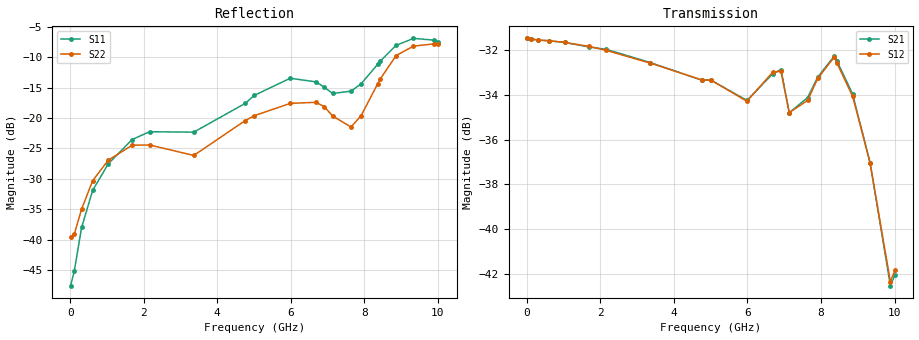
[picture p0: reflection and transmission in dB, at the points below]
! Device ID: PE43705
! Serial: 1
! Insertion: A
! Impedance: 50 ohm
! Temp: 25C
! VDD: 3.400V
! Attenuation Step: 30.50dB
#  Hz  S  RI  R  50
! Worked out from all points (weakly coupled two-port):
!   401 points, 10 MHz to 10.01 GHz, reference 50 ohm
!   highest |S21| = -31.47 dB at 10 MHz (marker M1); lowest = -42.5 dB at 9.885 GHz (marker M2)
!   lowest |S11| = -47.5 dB at 10 MHz (marker M3), VSWR 1.01, Z = 49.6 + j0.0403 ohm
!   |S11| at or under -10 dB: start of sweep to 8.525 GHz
!   |S22| runs from -39.6 to -7.8 dB; largest |S21 - S12| = 0.00087
!   S11 on the Smith chart (normalised r, x): 10 MHz: 0.99, +0.00; 4.76 GHz: 0.79, +0.12; 8.435 GHz: 0.79, +0.50; 9.335 GHz: 0.51, +0.52; 10.01 GHz: 0.46, +0.30
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1e7  -0.00419 0.000406  0.0267 -0.0001  0.0267 -0.000126  -0.0106 0.000549
1.1e8  -0.00389 0.00394  0.0266 -0.000711  0.0266 -0.00072  -0.00985 0.00519
3.1e8  -0.00643 0.0109  0.0264 -0.00193  0.0264 -0.00193  -0.0116 0.0136
6.1e8  -0.0161 0.0197  0.0261 -0.00375  0.0261 -0.00377  -0.0189 0.024
1.035e9  -0.0362 0.0214  0.0254 -0.00617  0.0254 -0.00621  -0.0344 0.0291
1.685e9  -0.066 0.00874  0.0237 -0.00953  0.0238 -0.0095  -0.0553 0.0227
2.16e9  -0.0769 -0.00592  0.0223 -0.0118  0.0222 -0.0117  -0.0586 0.0132
3.36e9  -0.0763 -0.00546  0.0173 -0.016  0.0173 -0.0159  -0.0467 0.0157
4.76e9  -0.1106 0.0718  0.0121 -0.0178  0.0123 -0.0177  -0.0783 0.0542
5.01e9  -0.1265 0.0868  0.0118 -0.018  0.0118 -0.018  -0.0867 0.0583
5.985e9  -0.181 0.11  0.00771 -0.0178  0.00773 -0.0177  -0.1149 0.0646
6.685e9  -0.1727 0.0962  0.00703 -0.0211  0.00704 -0.0213  -0.1238 0.0523
6.91e9  -0.154 0.0907  0.00387 -0.0224  0.00393 -0.0222  -0.1136 0.0493
7.135e9  -0.1394 0.0763  0.00334 -0.0179  0.00336 -0.0179  -0.0916 0.0491
7.635e9  -0.0907 0.1389  0.00384 -0.0193  0.0039 -0.019  -0.0499 0.0679
7.91e9  -0.0566 0.1817  0.00345 -0.0216  0.0037 -0.0214  -0.0368 0.0976
8.36e9  -0.0328 0.2735  -0.00359 -0.0241  -0.00355 -0.024  -0.0363 0.1866
8.435e9  -0.0353 0.2908  -0.00509 -0.0232  -0.00477 -0.023  -0.0404 0.2054
8.86e9  -0.0872 0.3837  -0.00976 -0.0175  -0.00945 -0.0174  -0.1039 0.3073
9.335e9  -0.1824 0.4112  -0.00888 -0.0109  -0.0086 -0.0111  -0.2089 0.328
9.885e9  -0.2994 0.3159  -0.00206 -0.00718  -0.00205 -0.00735  -0.3441 0.2132
1.001e10  -0.3164 0.275  0.000504 -0.00787  -0.000344 -0.00808  -0.3668 0.1634
